###############################################################
#  Generated by:      Cadence Innovus 21.14-s109_1
#  OS:                Linux x86_64(Host ID eecs2420p06.engin.umich.edu)
#  Generated on:      Fri Mar 24 00:08:22 2023
#  Design:            PE_top
#  Command:           write_lef_abstract /afs/umich.edu/class/eecs627/w23/groups/group4/CNN_LSTM/CNN/apr/PE_top/data/PE_top.lef -specifyTopLayer 4 -stripePin -PGpinLayers 4
###############################################################

VERSION 5.8 ;

BUSBITCHARS "[]" ;
DIVIDERCHAR "/" ;

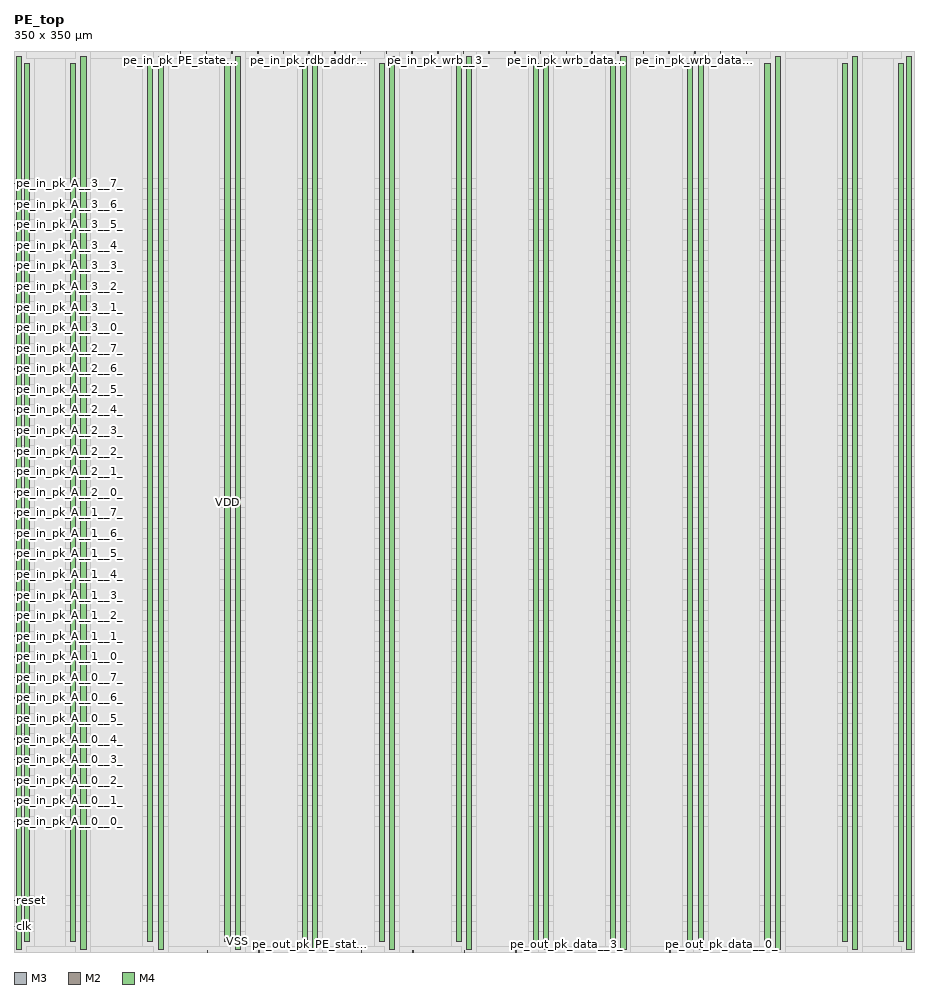
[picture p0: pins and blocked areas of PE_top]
MACRO PE_top
  CLASS BLOCK ;
  SIZE 350.000000 BY 350.000000 ;
  FOREIGN PE_top 0.000000 0.000000 ;
  ORIGIN 0 0 ;
  SYMMETRY X Y R90 ;
  PIN clk
    DIRECTION INPUT ;
    USE SIGNAL ;
    ANTENNAPARTIALMETALAREA 1.38 LAYER M3  ;
    ANTENNAPARTIALMETALSIDEAREA 0.0142 LAYER M3  ;
    ANTENNAMODEL OXIDE1 ;
    ANTENNAGATEAREA 0.8352 LAYER M3  ;
    ANTENNAMAXAREACAR 2.64655 LAYER M3  ;
    ANTENNAMAXSIDEAREACAR 0.0272749 LAYER M3  ;
    ANTENNAMAXCUTCAR 0.191571 LAYER V3  ;
    PORT
      LAYER M3 ;
        RECT 0.000000 9.900000 0.600000 10.100000 ;
    END
  END clk
  PIN reset
    DIRECTION INPUT ;
    USE SIGNAL ;
    ANTENNAPARTIALMETALAREA 4.46 LAYER M3  ;
    ANTENNAPARTIALMETALSIDEAREA 0.0454 LAYER M3  ;
    ANTENNAMODEL OXIDE1 ;
    ANTENNAGATEAREA 0.9552 LAYER M3  ;
    ANTENNAMAXAREACAR 56.4025 LAYER M3  ;
    ANTENNAMAXSIDEAREACAR 0.569324 LAYER M3  ;
    ANTENNAMAXCUTCAR 1.28205 LAYER V3  ;
    PORT
      LAYER M3 ;
        RECT 0.000000 19.900000 0.600000 20.100000 ;
    END
  END reset
  PIN pe_in_pk_PE_state__2_
    DIRECTION INPUT ;
    USE SIGNAL ;
    ANTENNAPARTIALMETALAREA 5.98 LAYER M2  ;
    ANTENNAPARTIALMETALSIDEAREA 0.0598 LAYER M2  ;
    ANTENNAPARTIALCUTAREA 0.04 LAYER V2  ;
    ANTENNAPARTIALMETALAREA 0.24 LAYER M3  ;
    ANTENNAPARTIALMETALSIDEAREA 0.0032 LAYER M3  ;
    ANTENNAMODEL OXIDE1 ;
    ANTENNAGATEAREA 0.0624 LAYER M3  ;
    ANTENNAMAXAREACAR 33.8462 LAYER M3  ;
    ANTENNAMAXSIDEAREACAR 0.358333 LAYER M3  ;
    ANTENNAMAXCUTCAR 1.28205 LAYER V3  ;
    PORT
      LAYER M2 ;
        RECT 84.700000 349.400000 84.900000 350.000000 ;
    END
  END pe_in_pk_PE_state__2_
  PIN pe_in_pk_PE_state__1_
    DIRECTION INPUT ;
    USE SIGNAL ;
    ANTENNAPARTIALMETALAREA 5.1 LAYER M2  ;
    ANTENNAPARTIALMETALSIDEAREA 0.051 LAYER M2  ;
    ANTENNAPARTIALCUTAREA 0.08 LAYER V2  ;
    ANTENNAPARTIALMETALAREA 1.24 LAYER M3  ;
    ANTENNAPARTIALMETALSIDEAREA 0.0128 LAYER M3  ;
    ANTENNAMODEL OXIDE1 ;
    ANTENNAGATEAREA 0.0624 LAYER M3  ;
    ANTENNAMAXAREACAR 87.0513 LAYER M3  ;
    ANTENNAMAXSIDEAREACAR 0.883974 LAYER M3  ;
    ANTENNAMAXCUTCAR 1.92308 LAYER V3  ;
    PORT
      LAYER M2 ;
        RECT 74.700000 349.400000 74.900000 350.000000 ;
    END
  END pe_in_pk_PE_state__1_
  PIN pe_in_pk_PE_state__0_
    DIRECTION INPUT ;
    USE SIGNAL ;
    ANTENNAPARTIALMETALAREA 5.26 LAYER M2  ;
    ANTENNAPARTIALMETALSIDEAREA 0.0526 LAYER M2  ;
    ANTENNAPARTIALCUTAREA 0.08 LAYER V2  ;
    ANTENNAPARTIALMETALAREA 2.6 LAYER M3  ;
    ANTENNAPARTIALMETALSIDEAREA 0.0264 LAYER M3  ;
    ANTENNAMODEL OXIDE1 ;
    ANTENNAGATEAREA 0.0624 LAYER M3  ;
    ANTENNAMAXAREACAR 106.282 LAYER M3  ;
    ANTENNAMAXSIDEAREACAR 1.07628 LAYER M3  ;
    ANTENNAMAXCUTCAR 1.92308 LAYER V3  ;
    PORT
      LAYER M2 ;
        RECT 64.700000 349.400000 64.900000 350.000000 ;
    END
  END pe_in_pk_PE_state__0_
  PIN pe_in_pk_A__3__7_
    DIRECTION INPUT ;
    USE SIGNAL ;
    ANTENNAPARTIALMETALAREA 8.54 LAYER M3  ;
    ANTENNAPARTIALMETALSIDEAREA 0.0854 LAYER M3  ;
    ANTENNAMODEL OXIDE1 ;
    ANTENNAGATEAREA 0.0624 LAYER M3  ;
    ANTENNAMAXAREACAR 169.423 LAYER M3  ;
    ANTENNAMAXSIDEAREACAR 1.70128 LAYER M3  ;
    ANTENNAMAXCUTCAR 1.92308 LAYER V3  ;
    PORT
      LAYER M3 ;
        RECT 0.000000 298.700000 0.600000 298.900000 ;
    END
  END pe_in_pk_A__3__7_
  PIN pe_in_pk_A__3__6_
    DIRECTION INPUT ;
    USE SIGNAL ;
    ANTENNAPARTIALMETALAREA 7.58 LAYER M3  ;
    ANTENNAPARTIALMETALSIDEAREA 0.0758 LAYER M3  ;
    ANTENNAMODEL OXIDE1 ;
    ANTENNAGATEAREA 0.0624 LAYER M3  ;
    ANTENNAMAXAREACAR 127.115 LAYER M3  ;
    ANTENNAMAXSIDEAREACAR 1.27821 LAYER M3  ;
    ANTENNAMAXCUTCAR 1.92308 LAYER V3  ;
    PORT
      LAYER M3 ;
        RECT 0.000000 290.700000 0.600000 290.900000 ;
    END
  END pe_in_pk_A__3__6_
  PIN pe_in_pk_A__3__5_
    DIRECTION INPUT ;
    USE SIGNAL ;
    ANTENNAPARTIALMETALAREA 6.54 LAYER M3  ;
    ANTENNAPARTIALMETALSIDEAREA 0.0654 LAYER M3  ;
    ANTENNAMODEL OXIDE1 ;
    ANTENNAGATEAREA 0.0624 LAYER M3  ;
    ANTENNAMAXAREACAR 121.987 LAYER M3  ;
    ANTENNAMAXSIDEAREACAR 1.22692 LAYER M3  ;
    ANTENNAMAXCUTCAR 1.92308 LAYER V3  ;
    PORT
      LAYER M3 ;
        RECT 0.000000 282.700000 0.600000 282.900000 ;
    END
  END pe_in_pk_A__3__5_
  PIN pe_in_pk_A__3__4_
    DIRECTION INPUT ;
    USE SIGNAL ;
    ANTENNAPARTIALMETALAREA 6.14 LAYER M3  ;
    ANTENNAPARTIALMETALSIDEAREA 0.0614 LAYER M3  ;
    ANTENNAMODEL OXIDE1 ;
    ANTENNAGATEAREA 0.0624 LAYER M3  ;
    ANTENNAMAXAREACAR 113.013 LAYER M3  ;
    ANTENNAMAXSIDEAREACAR 1.13718 LAYER M3  ;
    ANTENNAMAXCUTCAR 1.92308 LAYER V3  ;
    PORT
      LAYER M3 ;
        RECT 0.000000 274.700000 0.600000 274.900000 ;
    END
  END pe_in_pk_A__3__4_
  PIN pe_in_pk_A__3__3_
    DIRECTION INPUT ;
    USE SIGNAL ;
    ANTENNAPARTIALMETALAREA 6.14 LAYER M3  ;
    ANTENNAPARTIALMETALSIDEAREA 0.0614 LAYER M3  ;
    ANTENNAMODEL OXIDE1 ;
    ANTENNAGATEAREA 0.0624 LAYER M3  ;
    ANTENNAMAXAREACAR 106.603 LAYER M3  ;
    ANTENNAMAXSIDEAREACAR 1.07308 LAYER M3  ;
    ANTENNAMAXCUTCAR 1.92308 LAYER V3  ;
    PORT
      LAYER M3 ;
        RECT 0.000000 266.700000 0.600000 266.900000 ;
    END
  END pe_in_pk_A__3__3_
  PIN pe_in_pk_A__3__2_
    DIRECTION INPUT ;
    USE SIGNAL ;
    ANTENNAPARTIALMETALAREA 6.22 LAYER M3  ;
    ANTENNAPARTIALMETALSIDEAREA 0.0622 LAYER M3  ;
    ANTENNAMODEL OXIDE1 ;
    ANTENNAGATEAREA 0.0624 LAYER M3  ;
    ANTENNAMAXAREACAR 107.885 LAYER M3  ;
    ANTENNAMAXSIDEAREACAR 1.0859 LAYER M3  ;
    ANTENNAMAXCUTCAR 1.92308 LAYER V3  ;
    PORT
      LAYER M3 ;
        RECT 0.000000 258.700000 0.600000 258.900000 ;
    END
  END pe_in_pk_A__3__2_
  PIN pe_in_pk_A__3__1_
    DIRECTION INPUT ;
    USE SIGNAL ;
    ANTENNAPARTIALMETALAREA 6.38 LAYER M3  ;
    ANTENNAPARTIALMETALSIDEAREA 0.0638 LAYER M3  ;
    ANTENNAMODEL OXIDE1 ;
    ANTENNAGATEAREA 0.0624 LAYER M3  ;
    ANTENNAMAXAREACAR 109.167 LAYER M3  ;
    ANTENNAMAXSIDEAREACAR 1.09872 LAYER M3  ;
    ANTENNAMAXCUTCAR 1.92308 LAYER V3  ;
    PORT
      LAYER M3 ;
        RECT 0.000000 250.700000 0.600000 250.900000 ;
    END
  END pe_in_pk_A__3__1_
  PIN pe_in_pk_A__3__0_
    DIRECTION INPUT ;
    USE SIGNAL ;
    ANTENNAPARTIALMETALAREA 6.38 LAYER M3  ;
    ANTENNAPARTIALMETALSIDEAREA 0.0638 LAYER M3  ;
    ANTENNAMODEL OXIDE1 ;
    ANTENNAGATEAREA 0.0624 LAYER M3  ;
    ANTENNAMAXAREACAR 106.603 LAYER M3  ;
    ANTENNAMAXSIDEAREACAR 1.07308 LAYER M3  ;
    ANTENNAMAXCUTCAR 1.92308 LAYER V3  ;
    PORT
      LAYER M3 ;
        RECT 0.000000 242.700000 0.600000 242.900000 ;
    END
  END pe_in_pk_A__3__0_
  PIN pe_in_pk_A__2__7_
    DIRECTION INPUT ;
    USE SIGNAL ;
    ANTENNAPARTIALMETALAREA 6.46 LAYER M3  ;
    ANTENNAPARTIALMETALSIDEAREA 0.0646 LAYER M3  ;
    ANTENNAMODEL OXIDE1 ;
    ANTENNAGATEAREA 0.0624 LAYER M3  ;
    ANTENNAMAXAREACAR 114.295 LAYER M3  ;
    ANTENNAMAXSIDEAREACAR 1.15 LAYER M3  ;
    ANTENNAMAXCUTCAR 1.92308 LAYER V3  ;
    PORT
      LAYER M3 ;
        RECT 0.000000 234.700000 0.600000 234.900000 ;
    END
  END pe_in_pk_A__2__7_
  PIN pe_in_pk_A__2__6_
    DIRECTION INPUT ;
    USE SIGNAL ;
    ANTENNAPARTIALMETALAREA 6.62 LAYER M3  ;
    ANTENNAPARTIALMETALSIDEAREA 0.0662 LAYER M3  ;
    ANTENNAMODEL OXIDE1 ;
    ANTENNAGATEAREA 0.0624 LAYER M3  ;
    ANTENNAMAXAREACAR 115.577 LAYER M3  ;
    ANTENNAMAXSIDEAREACAR 1.16282 LAYER M3  ;
    ANTENNAMAXCUTCAR 1.92308 LAYER V3  ;
    PORT
      LAYER M3 ;
        RECT 0.000000 226.700000 0.600000 226.900000 ;
    END
  END pe_in_pk_A__2__6_
  PIN pe_in_pk_A__2__5_
    DIRECTION INPUT ;
    USE SIGNAL ;
    ANTENNAPARTIALMETALAREA 6.46 LAYER M3  ;
    ANTENNAPARTIALMETALSIDEAREA 0.0646 LAYER M3  ;
    ANTENNAMODEL OXIDE1 ;
    ANTENNAGATEAREA 0.0624 LAYER M3  ;
    ANTENNAMAXAREACAR 113.013 LAYER M3  ;
    ANTENNAMAXSIDEAREACAR 1.13718 LAYER M3  ;
    ANTENNAMAXCUTCAR 1.92308 LAYER V3  ;
    PORT
      LAYER M3 ;
        RECT 0.000000 218.700000 0.600000 218.900000 ;
    END
  END pe_in_pk_A__2__5_
  PIN pe_in_pk_A__2__4_
    DIRECTION INPUT ;
    USE SIGNAL ;
    ANTENNAPARTIALMETALAREA 6.46 LAYER M3  ;
    ANTENNAPARTIALMETALSIDEAREA 0.0646 LAYER M3  ;
    ANTENNAMODEL OXIDE1 ;
    ANTENNAGATEAREA 0.0624 LAYER M3  ;
    ANTENNAMAXAREACAR 107.885 LAYER M3  ;
    ANTENNAMAXSIDEAREACAR 1.0859 LAYER M3  ;
    ANTENNAMAXCUTCAR 1.92308 LAYER V3  ;
    PORT
      LAYER M3 ;
        RECT 0.000000 210.700000 0.600000 210.900000 ;
    END
  END pe_in_pk_A__2__4_
  PIN pe_in_pk_A__2__3_
    DIRECTION INPUT ;
    USE SIGNAL ;
    ANTENNAPARTIALMETALAREA 6.54 LAYER M3  ;
    ANTENNAPARTIALMETALSIDEAREA 0.0654 LAYER M3  ;
    ANTENNAMODEL OXIDE1 ;
    ANTENNAGATEAREA 0.0624 LAYER M3  ;
    ANTENNAMAXAREACAR 110.449 LAYER M3  ;
    ANTENNAMAXSIDEAREACAR 1.11154 LAYER M3  ;
    ANTENNAMAXCUTCAR 1.92308 LAYER V3  ;
    PORT
      LAYER M3 ;
        RECT 0.000000 202.700000 0.600000 202.900000 ;
    END
  END pe_in_pk_A__2__3_
  PIN pe_in_pk_A__2__2_
    DIRECTION INPUT ;
    USE SIGNAL ;
    ANTENNAPARTIALMETALAREA 5.1 LAYER M3  ;
    ANTENNAPARTIALMETALSIDEAREA 0.051 LAYER M3  ;
    ANTENNAMODEL OXIDE1 ;
    ANTENNAGATEAREA 0.0624 LAYER M3  ;
    ANTENNAMAXAREACAR 91.2179 LAYER M3  ;
    ANTENNAMAXSIDEAREACAR 0.919231 LAYER M3  ;
    ANTENNAMAXCUTCAR 1.92308 LAYER V3  ;
    PORT
      LAYER M3 ;
        RECT 0.000000 194.700000 0.600000 194.900000 ;
    END
  END pe_in_pk_A__2__2_
  PIN pe_in_pk_A__2__1_
    DIRECTION INPUT ;
    USE SIGNAL ;
    ANTENNAPARTIALMETALAREA 4.06 LAYER M3  ;
    ANTENNAPARTIALMETALSIDEAREA 0.0406 LAYER M3  ;
    ANTENNAMODEL OXIDE1 ;
    ANTENNAGATEAREA 0.0624 LAYER M3  ;
    ANTENNAMAXAREACAR 74.5513 LAYER M3  ;
    ANTENNAMAXSIDEAREACAR 0.752564 LAYER M3  ;
    ANTENNAMAXCUTCAR 1.92308 LAYER V3  ;
    PORT
      LAYER M3 ;
        RECT 0.000000 186.700000 0.600000 186.900000 ;
    END
  END pe_in_pk_A__2__1_
  PIN pe_in_pk_A__2__0_
    DIRECTION INPUT ;
    USE SIGNAL ;
    ANTENNAPARTIALMETALAREA 3.34 LAYER M3  ;
    ANTENNAPARTIALMETALSIDEAREA 0.0334 LAYER M3  ;
    ANTENNAMODEL OXIDE1 ;
    ANTENNAGATEAREA 0.0624 LAYER M3  ;
    ANTENNAMAXAREACAR 66.859 LAYER M3  ;
    ANTENNAMAXSIDEAREACAR 0.675641 LAYER M3  ;
    ANTENNAMAXCUTCAR 1.92308 LAYER V3  ;
    PORT
      LAYER M3 ;
        RECT 0.000000 178.700000 0.600000 178.900000 ;
    END
  END pe_in_pk_A__2__0_
  PIN pe_in_pk_A__1__7_
    DIRECTION INPUT ;
    USE SIGNAL ;
    ANTENNAPARTIALMETALAREA 2.22 LAYER M3  ;
    ANTENNAPARTIALMETALSIDEAREA 0.0222 LAYER M3  ;
    ANTENNAMODEL OXIDE1 ;
    ANTENNAGATEAREA 0.0624 LAYER M3  ;
    ANTENNAMAXAREACAR 48.9103 LAYER M3  ;
    ANTENNAMAXSIDEAREACAR 0.496154 LAYER M3  ;
    ANTENNAMAXCUTCAR 1.92308 LAYER V3  ;
    PORT
      LAYER M3 ;
        RECT 0.000000 170.700000 0.600000 170.900000 ;
    END
  END pe_in_pk_A__1__7_
  PIN pe_in_pk_A__1__6_
    DIRECTION INPUT ;
    USE SIGNAL ;
    ANTENNAPARTIALMETALAREA 1.58 LAYER M3  ;
    ANTENNAPARTIALMETALSIDEAREA 0.0158 LAYER M3  ;
    ANTENNAMODEL OXIDE1 ;
    ANTENNAGATEAREA 0.0624 LAYER M3  ;
    ANTENNAMAXAREACAR 30.9615 LAYER M3  ;
    ANTENNAMAXSIDEAREACAR 0.316667 LAYER M3  ;
    ANTENNAMAXCUTCAR 1.92308 LAYER V3  ;
    PORT
      LAYER M3 ;
        RECT 0.000000 162.700000 0.600000 162.900000 ;
    END
  END pe_in_pk_A__1__6_
  PIN pe_in_pk_A__1__5_
    DIRECTION INPUT ;
    USE SIGNAL ;
    ANTENNAPARTIALMETALAREA 1.66 LAYER M3  ;
    ANTENNAPARTIALMETALSIDEAREA 0.0166 LAYER M3  ;
    ANTENNAMODEL OXIDE1 ;
    ANTENNAGATEAREA 0.0624 LAYER M3  ;
    ANTENNAMAXAREACAR 34.8077 LAYER M3  ;
    ANTENNAMAXSIDEAREACAR 0.355128 LAYER M3  ;
    ANTENNAMAXCUTCAR 1.92308 LAYER V3  ;
    PORT
      LAYER M3 ;
        RECT 0.000000 154.700000 0.600000 154.900000 ;
    END
  END pe_in_pk_A__1__5_
  PIN pe_in_pk_A__1__4_
    DIRECTION INPUT ;
    USE SIGNAL ;
    ANTENNAPARTIALMETALAREA 1.74 LAYER M3  ;
    ANTENNAPARTIALMETALSIDEAREA 0.0174 LAYER M3  ;
    ANTENNAMODEL OXIDE1 ;
    ANTENNAGATEAREA 0.0624 LAYER M3  ;
    ANTENNAMAXAREACAR 33.5256 LAYER M3  ;
    ANTENNAMAXSIDEAREACAR 0.342308 LAYER M3  ;
    ANTENNAMAXCUTCAR 1.92308 LAYER V3  ;
    PORT
      LAYER M3 ;
        RECT 0.000000 146.700000 0.600000 146.900000 ;
    END
  END pe_in_pk_A__1__4_
  PIN pe_in_pk_A__1__3_
    DIRECTION INPUT ;
    USE SIGNAL ;
    ANTENNAPARTIALMETALAREA 1.66 LAYER M3  ;
    ANTENNAPARTIALMETALSIDEAREA 0.0166 LAYER M3  ;
    ANTENNAMODEL OXIDE1 ;
    ANTENNAGATEAREA 0.0624 LAYER M3  ;
    ANTENNAMAXAREACAR 30.9615 LAYER M3  ;
    ANTENNAMAXSIDEAREACAR 0.316667 LAYER M3  ;
    ANTENNAMAXCUTCAR 1.92308 LAYER V3  ;
    PORT
      LAYER M3 ;
        RECT 0.000000 138.700000 0.600000 138.900000 ;
    END
  END pe_in_pk_A__1__3_
  PIN pe_in_pk_A__1__2_
    DIRECTION INPUT ;
    USE SIGNAL ;
    ANTENNAPARTIALMETALAREA 1.74 LAYER M3  ;
    ANTENNAPARTIALMETALSIDEAREA 0.0174 LAYER M3  ;
    ANTENNAMODEL OXIDE1 ;
    ANTENNAGATEAREA 0.0624 LAYER M3  ;
    ANTENNAMAXAREACAR 45.0641 LAYER M3  ;
    ANTENNAMAXSIDEAREACAR 0.457692 LAYER M3  ;
    ANTENNAMAXCUTCAR 1.92308 LAYER V3  ;
    PORT
      LAYER M3 ;
        RECT 0.000000 130.700000 0.600000 130.900000 ;
    END
  END pe_in_pk_A__1__2_
  PIN pe_in_pk_A__1__1_
    DIRECTION INPUT ;
    USE SIGNAL ;
    ANTENNAPARTIALMETALAREA 1.74 LAYER M3  ;
    ANTENNAPARTIALMETALSIDEAREA 0.0174 LAYER M3  ;
    ANTENNAMODEL OXIDE1 ;
    ANTENNAGATEAREA 0.0624 LAYER M3  ;
    ANTENNAMAXAREACAR 39.9359 LAYER M3  ;
    ANTENNAMAXSIDEAREACAR 0.40641 LAYER M3  ;
    ANTENNAMAXCUTCAR 1.92308 LAYER V3  ;
    PORT
      LAYER M3 ;
        RECT 0.000000 122.700000 0.600000 122.900000 ;
    END
  END pe_in_pk_A__1__1_
  PIN pe_in_pk_A__1__0_
    DIRECTION INPUT ;
    USE SIGNAL ;
    ANTENNAPARTIALMETALAREA 2.54 LAYER M3  ;
    ANTENNAPARTIALMETALSIDEAREA 0.0254 LAYER M3  ;
    ANTENNAMODEL OXIDE1 ;
    ANTENNAGATEAREA 0.0624 LAYER M3  ;
    ANTENNAMAXAREACAR 50.1923 LAYER M3  ;
    ANTENNAMAXSIDEAREACAR 0.508974 LAYER M3  ;
    ANTENNAMAXCUTCAR 1.92308 LAYER V3  ;
    PORT
      LAYER M3 ;
        RECT 0.000000 114.700000 0.600000 114.900000 ;
    END
  END pe_in_pk_A__1__0_
  PIN pe_in_pk_A__0__7_
    DIRECTION INPUT ;
    USE SIGNAL ;
    ANTENNAPARTIALMETALAREA 3.34 LAYER M3  ;
    ANTENNAPARTIALMETALSIDEAREA 0.0334 LAYER M3  ;
    ANTENNAMODEL OXIDE1 ;
    ANTENNAGATEAREA 0.0624 LAYER M3  ;
    ANTENNAMAXAREACAR 60.4487 LAYER M3  ;
    ANTENNAMAXSIDEAREACAR 0.611538 LAYER M3  ;
    ANTENNAMAXCUTCAR 1.92308 LAYER V3  ;
    PORT
      LAYER M3 ;
        RECT 0.000000 106.700000 0.600000 106.900000 ;
    END
  END pe_in_pk_A__0__7_
  PIN pe_in_pk_A__0__6_
    DIRECTION INPUT ;
    USE SIGNAL ;
    ANTENNAPARTIALMETALAREA 3.34 LAYER M3  ;
    ANTENNAPARTIALMETALSIDEAREA 0.0334 LAYER M3  ;
    ANTENNAMODEL OXIDE1 ;
    ANTENNAGATEAREA 0.0624 LAYER M3  ;
    ANTENNAMAXAREACAR 66.859 LAYER M3  ;
    ANTENNAMAXSIDEAREACAR 0.675641 LAYER M3  ;
    ANTENNAMAXCUTCAR 1.92308 LAYER V3  ;
    PORT
      LAYER M3 ;
        RECT 0.000000 98.700000 0.600000 98.900000 ;
    END
  END pe_in_pk_A__0__6_
  PIN pe_in_pk_A__0__5_
    DIRECTION INPUT ;
    USE SIGNAL ;
    ANTENNAPARTIALMETALAREA 3.58 LAYER M3  ;
    ANTENNAPARTIALMETALSIDEAREA 0.0358 LAYER M3  ;
    ANTENNAMODEL OXIDE1 ;
    ANTENNAGATEAREA 0.0624 LAYER M3  ;
    ANTENNAMAXAREACAR 68.141 LAYER M3  ;
    ANTENNAMAXSIDEAREACAR 0.688462 LAYER M3  ;
    ANTENNAMAXCUTCAR 1.92308 LAYER V3  ;
    PORT
      LAYER M3 ;
        RECT 0.000000 90.700000 0.600000 90.900000 ;
    END
  END pe_in_pk_A__0__5_
  PIN pe_in_pk_A__0__4_
    DIRECTION INPUT ;
    USE SIGNAL ;
    ANTENNAPARTIALMETALAREA 3.9 LAYER M3  ;
    ANTENNAPARTIALMETALSIDEAREA 0.039 LAYER M3  ;
    ANTENNAMODEL OXIDE1 ;
    ANTENNAGATEAREA 0.0624 LAYER M3  ;
    ANTENNAMAXAREACAR 70.7051 LAYER M3  ;
    ANTENNAMAXSIDEAREACAR 0.714103 LAYER M3  ;
    ANTENNAMAXCUTCAR 1.92308 LAYER V3  ;
    PORT
      LAYER M3 ;
        RECT 0.000000 82.700000 0.600000 82.900000 ;
    END
  END pe_in_pk_A__0__4_
  PIN pe_in_pk_A__0__3_
    DIRECTION INPUT ;
    USE SIGNAL ;
    ANTENNAPARTIALMETALAREA 4.3 LAYER M3  ;
    ANTENNAPARTIALMETALSIDEAREA 0.043 LAYER M3  ;
    ANTENNAMODEL OXIDE1 ;
    ANTENNAGATEAREA 0.0624 LAYER M3  ;
    ANTENNAMAXAREACAR 74.5513 LAYER M3  ;
    ANTENNAMAXSIDEAREACAR 0.752564 LAYER M3  ;
    ANTENNAMAXCUTCAR 1.92308 LAYER V3  ;
    PORT
      LAYER M3 ;
        RECT 0.000000 74.700000 0.600000 74.900000 ;
    END
  END pe_in_pk_A__0__3_
  PIN pe_in_pk_A__0__2_
    DIRECTION INPUT ;
    USE SIGNAL ;
    ANTENNAPARTIALMETALAREA 2.06 LAYER M3  ;
    ANTENNAPARTIALMETALSIDEAREA 0.0206 LAYER M3  ;
    ANTENNAMODEL OXIDE1 ;
    ANTENNAGATEAREA 0.0624 LAYER M3  ;
    ANTENNAMAXAREACAR 59.1667 LAYER M3  ;
    ANTENNAMAXSIDEAREACAR 0.598718 LAYER M3  ;
    ANTENNAMAXCUTCAR 1.92308 LAYER V3  ;
    PORT
      LAYER M3 ;
        RECT 0.000000 66.700000 0.600000 66.900000 ;
    END
  END pe_in_pk_A__0__2_
  PIN pe_in_pk_A__0__1_
    DIRECTION INPUT ;
    USE SIGNAL ;
    ANTENNAPARTIALMETALAREA 2.06 LAYER M3  ;
    ANTENNAPARTIALMETALSIDEAREA 0.0206 LAYER M3  ;
    ANTENNAPARTIALCUTAREA 0.08 LAYER V3  ;
    ANTENNAPARTIALMETALAREA 0.36 LAYER M4  ;
    ANTENNAPARTIALMETALSIDEAREA 0.004 LAYER M4  ;
    ANTENNAMODEL OXIDE1 ;
    ANTENNAGATEAREA 0.0624 LAYER M4  ;
    ANTENNAMAXAREACAR 55.641 LAYER M4  ;
    ANTENNAMAXSIDEAREACAR 0.576282 LAYER M4  ;
    ANTENNAMAXCUTCAR 3.20513 LAYER V4  ;
    PORT
      LAYER M3 ;
        RECT 0.000000 58.700000 0.600000 58.900000 ;
    END
  END pe_in_pk_A__0__1_
  PIN pe_in_pk_A__0__0_
    DIRECTION INPUT ;
    USE SIGNAL ;
    ANTENNAPARTIALMETALAREA 4.78 LAYER M3  ;
    ANTENNAPARTIALMETALSIDEAREA 0.0478 LAYER M3  ;
    ANTENNAMODEL OXIDE1 ;
    ANTENNAGATEAREA 0.0624 LAYER M3  ;
    ANTENNAMAXAREACAR 133.526 LAYER M3  ;
    ANTENNAMAXSIDEAREACAR 1.34231 LAYER M3  ;
    ANTENNAMAXCUTCAR 1.92308 LAYER V3  ;
    PORT
      LAYER M3 ;
        RECT 0.000000 50.700000 0.600000 50.900000 ;
    END
  END pe_in_pk_A__0__0_
  PIN pe_in_pk_wrb_data__7_
    DIRECTION INPUT ;
    USE SIGNAL ;
    ANTENNAPARTIALMETALAREA 11.82 LAYER M2  ;
    ANTENNAPARTIALMETALSIDEAREA 0.1182 LAYER M2  ;
    ANTENNAPARTIALCUTAREA 0.08 LAYER V2  ;
    ANTENNAPARTIALMETALAREA 7.56 LAYER M3  ;
    ANTENNAPARTIALMETALSIDEAREA 0.076 LAYER M3  ;
    ANTENNAPARTIALCUTAREA 0.04 LAYER V3  ;
    ANTENNAPARTIALMETALAREA 19.12 LAYER M4  ;
    ANTENNAPARTIALMETALSIDEAREA 0.1928 LAYER M4  ;
    ANTENNAMODEL OXIDE1 ;
    ANTENNAGATEAREA 0.3792 LAYER M4  ;
    ANTENNAMAXAREACAR 111.191 LAYER M4  ;
    ANTENNAMAXSIDEAREACAR 1.136 LAYER M4  ;
    ANTENNAMAXCUTCAR 5.76923 LAYER V4  ;
    PORT
      LAYER M2 ;
        RECT 284.700000 349.400000 284.900000 350.000000 ;
    END
  END pe_in_pk_wrb_data__7_
  PIN pe_in_pk_wrb_data__6_
    DIRECTION INPUT ;
    USE SIGNAL ;
    ANTENNAPARTIALMETALAREA 8.86 LAYER M2  ;
    ANTENNAPARTIALMETALSIDEAREA 0.0886 LAYER M2  ;
    ANTENNAPARTIALCUTAREA 0.08 LAYER V2  ;
    ANTENNAPARTIALMETALAREA 9.48 LAYER M3  ;
    ANTENNAPARTIALMETALSIDEAREA 0.0952 LAYER M3  ;
    ANTENNAMODEL OXIDE1 ;
    ANTENNAGATEAREA 0.1272 LAYER M3  ;
    ANTENNAMAXAREACAR 78.3648 LAYER M3  ;
    ANTENNAMAXSIDEAREACAR 0.789937 LAYER M3  ;
    ANTENNAPARTIALCUTAREA 0.08 LAYER V3  ;
    ANTENNAMAXCUTCAR 1.88679 LAYER V3  ;
    ANTENNAPARTIALMETALAREA 24.44 LAYER M4  ;
    ANTENNAPARTIALMETALSIDEAREA 0.2448 LAYER M4  ;
    ANTENNAGATEAREA 0.444 LAYER M4  ;
    ANTENNAMAXAREACAR 133.41 LAYER M4  ;
    ANTENNAMAXSIDEAREACAR 1.34129 LAYER M4  ;
    ANTENNAMAXCUTCAR 3.20513 LAYER V4  ;
    PORT
      LAYER M2 ;
        RECT 274.700000 349.400000 274.900000 350.000000 ;
    END
  END pe_in_pk_wrb_data__6_
  PIN pe_in_pk_wrb_data__5_
    DIRECTION INPUT ;
    USE SIGNAL ;
    ANTENNAPARTIALMETALAREA 8.54 LAYER M2  ;
    ANTENNAPARTIALMETALSIDEAREA 0.0854 LAYER M2  ;
    ANTENNAPARTIALCUTAREA 0.08 LAYER V2  ;
    ANTENNAPARTIALMETALAREA 8.24 LAYER M3  ;
    ANTENNAPARTIALMETALSIDEAREA 0.0832 LAYER M3  ;
    ANTENNAMODEL OXIDE1 ;
    ANTENNAGATEAREA 0.0624 LAYER M3  ;
    ANTENNAMAXAREACAR 151.795 LAYER M3  ;
    ANTENNAMAXSIDEAREACAR 1.53782 LAYER M3  ;
    ANTENNAPARTIALCUTAREA 0.08 LAYER V3  ;
    ANTENNAMAXCUTCAR 4.48718 LAYER V3  ;
    ANTENNAPARTIALMETALAREA 26 LAYER M4  ;
    ANTENNAPARTIALMETALSIDEAREA 0.2608 LAYER M4  ;
    ANTENNAGATEAREA 0.3792 LAYER M4  ;
    ANTENNAMAXAREACAR 220.36 LAYER M4  ;
    ANTENNAMAXSIDEAREACAR 2.22558 LAYER M4  ;
    ANTENNAMAXCUTCAR 4.48718 LAYER V4  ;
    PORT
      LAYER M2 ;
        RECT 264.700000 349.400000 264.900000 350.000000 ;
    END
  END pe_in_pk_wrb_data__5_
  PIN pe_in_pk_wrb_data__4_
    DIRECTION INPUT ;
    USE SIGNAL ;
    ANTENNAPARTIALMETALAREA 17.18 LAYER M2  ;
    ANTENNAPARTIALMETALSIDEAREA 0.1718 LAYER M2  ;
    ANTENNAPARTIALCUTAREA 0.08 LAYER V2  ;
    ANTENNAPARTIALMETALAREA 6.36 LAYER M3  ;
    ANTENNAPARTIALMETALSIDEAREA 0.064 LAYER M3  ;
    ANTENNAMODEL OXIDE1 ;
    ANTENNAGATEAREA 0.1272 LAYER M3  ;
    ANTENNAMAXAREACAR 53.8365 LAYER M3  ;
    ANTENNAMAXSIDEAREACAR 0.544654 LAYER M3  ;
    ANTENNAPARTIALCUTAREA 0.08 LAYER V3  ;
    ANTENNAMAXCUTCAR 1.88679 LAYER V3  ;
    ANTENNAPARTIALMETALAREA 16.24 LAYER M4  ;
    ANTENNAPARTIALMETALSIDEAREA 0.1632 LAYER M4  ;
    ANTENNAGATEAREA 0.444 LAYER M4  ;
    ANTENNAMAXAREACAR 90.4131 LAYER M4  ;
    ANTENNAMAXSIDEAREACAR 0.912222 LAYER M4  ;
    ANTENNAMAXCUTCAR 4.48718 LAYER V4  ;
    PORT
      LAYER M2 ;
        RECT 254.700000 349.400000 254.900000 350.000000 ;
    END
  END pe_in_pk_wrb_data__4_
  PIN pe_in_pk_wrb_data__3_
    DIRECTION INPUT ;
    USE SIGNAL ;
    ANTENNAPARTIALMETALAREA 16.78 LAYER M2  ;
    ANTENNAPARTIALMETALSIDEAREA 0.1678 LAYER M2  ;
    ANTENNAPARTIALCUTAREA 0.08 LAYER V2  ;
    ANTENNAPARTIALMETALAREA 4.2 LAYER M3  ;
    ANTENNAPARTIALMETALSIDEAREA 0.0424 LAYER M3  ;
    ANTENNAMODEL OXIDE1 ;
    ANTENNAGATEAREA 0.0624 LAYER M3  ;
    ANTENNAMAXAREACAR 78.0769 LAYER M3  ;
    ANTENNAMAXSIDEAREACAR 0.794231 LAYER M3  ;
    ANTENNAPARTIALCUTAREA 0.08 LAYER V3  ;
    ANTENNAMAXCUTCAR 3.20513 LAYER V3  ;
    ANTENNAPARTIALMETALAREA 18.12 LAYER M4  ;
    ANTENNAPARTIALMETALSIDEAREA 0.1816 LAYER M4  ;
    ANTENNAGATEAREA 0.3792 LAYER M4  ;
    ANTENNAMAXAREACAR 125.862 LAYER M4  ;
    ANTENNAMAXSIDEAREACAR 1.27313 LAYER M4  ;
    ANTENNAMAXCUTCAR 3.20513 LAYER V4  ;
    PORT
      LAYER M2 ;
        RECT 244.700000 349.400000 244.900000 350.000000 ;
    END
  END pe_in_pk_wrb_data__3_
  PIN pe_in_pk_wrb_data__2_
    DIRECTION INPUT ;
    USE SIGNAL ;
    ANTENNAPARTIALMETALAREA 5.74 LAYER M2  ;
    ANTENNAPARTIALMETALSIDEAREA 0.0574 LAYER M2  ;
    ANTENNAPARTIALCUTAREA 0.08 LAYER V2  ;
    ANTENNAPARTIALMETALAREA 3.08 LAYER M3  ;
    ANTENNAPARTIALMETALSIDEAREA 0.0312 LAYER M3  ;
    ANTENNAPARTIALCUTAREA 0.08 LAYER V3  ;
    ANTENNAPARTIALMETALAREA 22.72 LAYER M4  ;
    ANTENNAPARTIALMETALSIDEAREA 0.228 LAYER M4  ;
    ANTENNAMODEL OXIDE1 ;
    ANTENNAGATEAREA 0.3792 LAYER M4  ;
    ANTENNAMAXAREACAR 129.98 LAYER M4  ;
    ANTENNAMAXSIDEAREACAR 1.31857 LAYER M4  ;
    ANTENNAMAXCUTCAR 4.48718 LAYER V4  ;
    PORT
      LAYER M2 ;
        RECT 234.700000 349.400000 234.900000 350.000000 ;
    END
  END pe_in_pk_wrb_data__2_
  PIN pe_in_pk_wrb_data__1_
    DIRECTION INPUT ;
    USE SIGNAL ;
    ANTENNAPARTIALMETALAREA 5.26 LAYER M2  ;
    ANTENNAPARTIALMETALSIDEAREA 0.0526 LAYER M2  ;
    ANTENNAPARTIALCUTAREA 0.08 LAYER V2  ;
    ANTENNAPARTIALMETALAREA 0.44 LAYER M3  ;
    ANTENNAPARTIALMETALSIDEAREA 0.0048 LAYER M3  ;
    ANTENNAPARTIALCUTAREA 0.08 LAYER V3  ;
    ANTENNAPARTIALMETALAREA 28.48 LAYER M4  ;
    ANTENNAPARTIALMETALSIDEAREA 0.2856 LAYER M4  ;
    ANTENNAMODEL OXIDE1 ;
    ANTENNAGATEAREA 0.3792 LAYER M4  ;
    ANTENNAMAXAREACAR 102.055 LAYER M4  ;
    ANTENNAMAXSIDEAREACAR 1.02738 LAYER M4  ;
    ANTENNAMAXCUTCAR 4.48718 LAYER V4  ;
    PORT
      LAYER M2 ;
        RECT 224.700000 349.400000 224.900000 350.000000 ;
    END
  END pe_in_pk_wrb_data__1_
  PIN pe_in_pk_wrb_data__0_
    DIRECTION INPUT ;
    USE SIGNAL ;
    ANTENNAPARTIALMETALAREA 6.7 LAYER M2  ;
    ANTENNAPARTIALMETALSIDEAREA 0.067 LAYER M2  ;
    ANTENNAPARTIALCUTAREA 0.08 LAYER V2  ;
    ANTENNAPARTIALMETALAREA 0.84 LAYER M3  ;
    ANTENNAPARTIALMETALSIDEAREA 0.0088 LAYER M3  ;
    ANTENNAPARTIALCUTAREA 0.08 LAYER V3  ;
    ANTENNAPARTIALMETALAREA 26.28 LAYER M4  ;
    ANTENNAPARTIALMETALSIDEAREA 0.2632 LAYER M4  ;
    ANTENNAMODEL OXIDE1 ;
    ANTENNAGATEAREA 0.3792 LAYER M4  ;
    ANTENNAMAXAREACAR 111.483 LAYER M4  ;
    ANTENNAMAXSIDEAREACAR 1.12935 LAYER M4  ;
    ANTENNAMAXCUTCAR 3.20513 LAYER V4  ;
    PORT
      LAYER M2 ;
        RECT 214.700000 349.400000 214.900000 350.000000 ;
    END
  END pe_in_pk_wrb_data__0_
  PIN pe_in_pk_wrb_addr__3_
    DIRECTION INPUT ;
    USE SIGNAL ;
    ANTENNAPARTIALMETALAREA 4.7 LAYER M2  ;
    ANTENNAPARTIALMETALSIDEAREA 0.047 LAYER M2  ;
    ANTENNAPARTIALCUTAREA 0.08 LAYER V2  ;
    ANTENNAPARTIALMETALAREA 0.84 LAYER M3  ;
    ANTENNAPARTIALMETALSIDEAREA 0.0088 LAYER M3  ;
    ANTENNAMODEL OXIDE1 ;
    ANTENNAGATEAREA 0.264 LAYER M3  ;
    ANTENNAMAXAREACAR 5.50152 LAYER M3  ;
    ANTENNAMAXSIDEAREACAR 0.0554545 LAYER M3  ;
    ANTENNAPARTIALCUTAREA 0.08 LAYER V3  ;
    ANTENNAMAXCUTCAR 0.909091 LAYER V3  ;
    ANTENNAPARTIALMETALAREA 27.32 LAYER M4  ;
    ANTENNAPARTIALMETALSIDEAREA 0.2736 LAYER M4  ;
    ANTENNAGATEAREA 1.056 LAYER M4  ;
    ANTENNAMAXAREACAR 41.6758 LAYER M4  ;
    ANTENNAMAXSIDEAREACAR 0.417576 LAYER M4  ;
    ANTENNAMAXCUTCAR 0.909091 LAYER V4  ;
    PORT
      LAYER M2 ;
        RECT 204.700000 349.400000 204.900000 350.000000 ;
    END
  END pe_in_pk_wrb_addr__3_
  PIN pe_in_pk_wrb_addr__2_
    DIRECTION INPUT ;
    USE SIGNAL ;
    ANTENNAPARTIALMETALAREA 4.78 LAYER M2  ;
    ANTENNAPARTIALMETALSIDEAREA 0.0478 LAYER M2  ;
    ANTENNAPARTIALCUTAREA 0.08 LAYER V2  ;
    ANTENNAPARTIALMETALAREA 4.32 LAYER M3  ;
    ANTENNAPARTIALMETALSIDEAREA 0.044 LAYER M3  ;
    ANTENNAMODEL OXIDE1 ;
    ANTENNAGATEAREA 0.8136 LAYER M3  ;
    ANTENNAMAXAREACAR 14.1259 LAYER M3  ;
    ANTENNAMAXSIDEAREACAR 0.142056 LAYER M3  ;
    ANTENNAPARTIALCUTAREA 0.08 LAYER V3  ;
    ANTENNAMAXCUTCAR 1.38038 LAYER V3  ;
    ANTENNAPARTIALMETALAREA 25.92 LAYER M4  ;
    ANTENNAPARTIALMETALSIDEAREA 0.26 LAYER M4  ;
    ANTENNAGATEAREA 1.7808 LAYER M4  ;
    ANTENNAMAXAREACAR 28.6812 LAYER M4  ;
    ANTENNAMAXSIDEAREACAR 0.288058 LAYER M4  ;
    ANTENNAMAXCUTCAR 2.25225 LAYER V4  ;
    PORT
      LAYER M2 ;
        RECT 194.700000 349.400000 194.900000 350.000000 ;
    END
  END pe_in_pk_wrb_addr__2_
  PIN pe_in_pk_wrb_addr__1_
    DIRECTION INPUT ;
    USE SIGNAL ;
    ANTENNAPARTIALMETALAREA 4.74 LAYER M2  ;
    ANTENNAPARTIALMETALSIDEAREA 0.0478 LAYER M2  ;
    ANTENNAMODEL OXIDE1 ;
    ANTENNAGATEAREA 0.1608 LAYER M2  ;
    ANTENNAMAXAREACAR 30.2736 LAYER M2  ;
    ANTENNAMAXSIDEAREACAR 0.306219 LAYER M2  ;
    ANTENNAPARTIALCUTAREA 0.08 LAYER V2  ;
    ANTENNAMAXCUTCAR 0.746269 LAYER V2  ;
    ANTENNAPARTIALMETALAREA 0.76 LAYER M3  ;
    ANTENNAPARTIALMETALSIDEAREA 0.008 LAYER M3  ;
    ANTENNAGATEAREA 0.3384 LAYER M3  ;
    ANTENNAMAXAREACAR 32.5195 LAYER M3  ;
    ANTENNAMAXSIDEAREACAR 0.32986 LAYER M3  ;
    ANTENNAMAXCUTCAR 0.746269 LAYER V3  ;
    PORT
      LAYER M2 ;
        RECT 184.700000 349.400000 184.900000 350.000000 ;
    END
  END pe_in_pk_wrb_addr__1_
  PIN pe_in_pk_wrb_addr__0_
    DIRECTION INPUT ;
    USE SIGNAL ;
    ANTENNAPARTIALMETALAREA 4.14 LAYER M2  ;
    ANTENNAPARTIALMETALSIDEAREA 0.0414 LAYER M2  ;
    ANTENNAPARTIALCUTAREA 0.08 LAYER V2  ;
    ANTENNAPARTIALMETALAREA 1.4 LAYER M3  ;
    ANTENNAPARTIALMETALSIDEAREA 0.0144 LAYER M3  ;
    ANTENNAMODEL OXIDE1 ;
    ANTENNAGATEAREA 0.1776 LAYER M3  ;
    ANTENNAMAXAREACAR 11.0011 LAYER M3  ;
    ANTENNAMAXSIDEAREACAR 0.113739 LAYER M3  ;
    ANTENNAPARTIALCUTAREA 0.08 LAYER V3  ;
    ANTENNAMAXCUTCAR 1.35135 LAYER V3  ;
    ANTENNAPARTIALMETALAREA 1.56 LAYER M4  ;
    ANTENNAPARTIALMETALSIDEAREA 0.016 LAYER M4  ;
    ANTENNAGATEAREA 0.7512 LAYER M4  ;
    ANTENNAMAXAREACAR 14.2696 LAYER M4  ;
    ANTENNAMAXSIDEAREACAR 0.148447 LAYER M4  ;
    ANTENNAMAXCUTCAR 1.35135 LAYER V4  ;
    PORT
      LAYER M2 ;
        RECT 174.700000 349.400000 174.900000 350.000000 ;
    END
  END pe_in_pk_wrb_addr__0_
  PIN pe_in_pk_wrb__3_
    DIRECTION INPUT ;
    USE SIGNAL ;
    ANTENNAPARTIALMETALAREA 3.9 LAYER M2  ;
    ANTENNAPARTIALMETALSIDEAREA 0.039 LAYER M2  ;
    ANTENNAPARTIALCUTAREA 0.08 LAYER V2  ;
    ANTENNAPARTIALMETALAREA 3.16 LAYER M3  ;
    ANTENNAPARTIALMETALSIDEAREA 0.0328 LAYER M3  ;
    ANTENNAMODEL OXIDE1 ;
    ANTENNAGATEAREA 0.4608 LAYER M3  ;
    ANTENNAMAXAREACAR 13.5236 LAYER M3  ;
    ANTENNAMAXSIDEAREACAR 0.141073 LAYER M3  ;
    ANTENNAMAXCUTCAR 1.34409 LAYER V3  ;
    PORT
      LAYER M2 ;
        RECT 164.700000 349.400000 164.900000 350.000000 ;
    END
  END pe_in_pk_wrb__3_
  PIN pe_in_pk_wrb__2_
    DIRECTION INPUT ;
    USE SIGNAL ;
    ANTENNAPARTIALMETALAREA 3.58 LAYER M2  ;
    ANTENNAPARTIALMETALSIDEAREA 0.0358 LAYER M2  ;
    ANTENNAPARTIALCUTAREA 0.08 LAYER V2  ;
    ANTENNAPARTIALMETALAREA 11.16 LAYER M3  ;
    ANTENNAPARTIALMETALSIDEAREA 0.112 LAYER M3  ;
    ANTENNAPARTIALCUTAREA 0.08 LAYER V3  ;
    ANTENNAPARTIALMETALAREA 14.76 LAYER M4  ;
    ANTENNAPARTIALMETALSIDEAREA 0.148 LAYER M4  ;
    ANTENNAMODEL OXIDE1 ;
    ANTENNAGATEAREA 0.4608 LAYER M4  ;
    ANTENNAMAXAREACAR 38.6838 LAYER M4  ;
    ANTENNAMAXSIDEAREACAR 0.3904 LAYER M4  ;
    ANTENNAMAXCUTCAR 0.980063 LAYER V4  ;
    PORT
      LAYER M2 ;
        RECT 154.700000 349.400000 154.900000 350.000000 ;
    END
  END pe_in_pk_wrb__2_
  PIN pe_in_pk_wrb__1_
    DIRECTION INPUT ;
    USE SIGNAL ;
    ANTENNAPARTIALMETALAREA 2.7 LAYER M2  ;
    ANTENNAPARTIALMETALSIDEAREA 0.027 LAYER M2  ;
    ANTENNAPARTIALCUTAREA 0.08 LAYER V2  ;
    ANTENNAPARTIALMETALAREA 8.68 LAYER M3  ;
    ANTENNAPARTIALMETALSIDEAREA 0.0872 LAYER M3  ;
    ANTENNAPARTIALCUTAREA 0.08 LAYER V3  ;
    ANTENNAPARTIALMETALAREA 30.44 LAYER M4  ;
    ANTENNAPARTIALMETALSIDEAREA 0.3048 LAYER M4  ;
    ANTENNAMODEL OXIDE1 ;
    ANTENNAGATEAREA 0.4608 LAYER M4  ;
    ANTENNAMAXAREACAR 71.7149 LAYER M4  ;
    ANTENNAMAXSIDEAREACAR 0.724362 LAYER M4  ;
    ANTENNAMAXCUTCAR 1.34409 LAYER V4  ;
    PORT
      LAYER M2 ;
        RECT 144.700000 349.400000 144.900000 350.000000 ;
    END
  END pe_in_pk_wrb__1_
  PIN pe_in_pk_wrb__0_
    DIRECTION INPUT ;
    USE SIGNAL ;
    ANTENNAPARTIALMETALAREA 2.86 LAYER M2  ;
    ANTENNAPARTIALMETALSIDEAREA 0.0286 LAYER M2  ;
    ANTENNAPARTIALCUTAREA 0.08 LAYER V2  ;
    ANTENNAPARTIALMETALAREA 18.52 LAYER M3  ;
    ANTENNAPARTIALMETALSIDEAREA 0.1856 LAYER M3  ;
    ANTENNAPARTIALCUTAREA 0.08 LAYER V3  ;
    ANTENNAPARTIALMETALAREA 34.36 LAYER M4  ;
    ANTENNAPARTIALMETALSIDEAREA 0.344 LAYER M4  ;
    ANTENNAMODEL OXIDE1 ;
    ANTENNAGATEAREA 0.4608 LAYER M4  ;
    ANTENNAMAXAREACAR 82.1232 LAYER M4  ;
    ANTENNAMAXSIDEAREACAR 0.826624 LAYER M4  ;
    ANTENNAMAXCUTCAR 0.980063 LAYER V4  ;
    PORT
      LAYER M2 ;
        RECT 134.700000 349.400000 134.900000 350.000000 ;
    END
  END pe_in_pk_wrb__0_
  PIN pe_in_pk_rdb_addr__3_
    DIRECTION INPUT ;
    USE SIGNAL ;
    ANTENNAPARTIALMETALAREA 2.7 LAYER M2  ;
    ANTENNAPARTIALMETALSIDEAREA 0.027 LAYER M2  ;
    ANTENNAPARTIALCUTAREA 0.08 LAYER V2  ;
    ANTENNAPARTIALMETALAREA 9.4 LAYER M3  ;
    ANTENNAPARTIALMETALSIDEAREA 0.0944 LAYER M3  ;
    ANTENNAPARTIALCUTAREA 0.08 LAYER V3  ;
    ANTENNAPARTIALMETALAREA 33.2 LAYER M4  ;
    ANTENNAPARTIALMETALSIDEAREA 0.3328 LAYER M4  ;
    ANTENNAMODEL OXIDE1 ;
    ANTENNAGATEAREA 1.1304 LAYER M4  ;
    ANTENNAMAXAREACAR 73.3278 LAYER M4  ;
    ANTENNAMAXSIDEAREACAR 0.737551 LAYER M4  ;
    ANTENNAMAXCUTCAR 3.72792 LAYER V4  ;
    PORT
      LAYER M2 ;
        RECT 124.700000 349.400000 124.900000 350.000000 ;
    END
  END pe_in_pk_rdb_addr__3_
  PIN pe_in_pk_rdb_addr__2_
    DIRECTION INPUT ;
    USE SIGNAL ;
    ANTENNAPARTIALMETALAREA 0.16 LAYER M2  ;
    ANTENNAPARTIALMETALSIDEAREA 0.0016 LAYER M2  ;
    ANTENNAPARTIALCUTAREA 0.08 LAYER V2  ;
    ANTENNAPARTIALMETALAREA 10.12 LAYER M3  ;
    ANTENNAPARTIALMETALSIDEAREA 0.1016 LAYER M3  ;
    ANTENNAPARTIALCUTAREA 0.08 LAYER V3  ;
    ANTENNAPARTIALMETALAREA 44.48 LAYER M4  ;
    ANTENNAPARTIALMETALSIDEAREA 0.4472 LAYER M4  ;
    ANTENNAMODEL OXIDE1 ;
    ANTENNAGATEAREA 2.472 LAYER M4  ;
    ANTENNAMAXAREACAR 65.0791 LAYER M4  ;
    ANTENNAMAXSIDEAREACAR 0.657821 LAYER M4  ;
    ANTENNAMAXCUTCAR 1.6983 LAYER V4  ;
    PORT
      LAYER M2 ;
        RECT 114.700000 349.400000 114.900000 350.000000 ;
    END
  END pe_in_pk_rdb_addr__2_
  PIN pe_in_pk_rdb_addr__1_
    DIRECTION INPUT ;
    USE SIGNAL ;
    ANTENNAPARTIALMETALAREA 6.06 LAYER M2  ;
    ANTENNAPARTIALMETALSIDEAREA 0.0606 LAYER M2  ;
    ANTENNAPARTIALCUTAREA 0.08 LAYER V2  ;
    ANTENNAPARTIALMETALAREA 3.08 LAYER M3  ;
    ANTENNAPARTIALMETALSIDEAREA 0.0312 LAYER M3  ;
    ANTENNAMODEL OXIDE1 ;
    ANTENNAGATEAREA 0.7992 LAYER M3  ;
    ANTENNAMAXAREACAR 10.0901 LAYER M3  ;
    ANTENNAMAXSIDEAREACAR 0.1 LAYER M3  ;
    ANTENNAMAXCUTCAR 0.15015 LAYER V3  ;
    PORT
      LAYER M2 ;
        RECT 104.700000 349.400000 104.900000 350.000000 ;
    END
  END pe_in_pk_rdb_addr__1_
  PIN pe_in_pk_rdb_addr__0_
    DIRECTION INPUT ;
    USE SIGNAL ;
    ANTENNAPARTIALMETALAREA 11.42 LAYER M2  ;
    ANTENNAPARTIALMETALSIDEAREA 0.1142 LAYER M2  ;
    ANTENNAPARTIALCUTAREA 0.08 LAYER V2  ;
    ANTENNAPARTIALMETALAREA 9.64 LAYER M3  ;
    ANTENNAPARTIALMETALSIDEAREA 0.0968 LAYER M3  ;
    ANTENNAMODEL OXIDE1 ;
    ANTENNAGATEAREA 0.576 LAYER M3  ;
    ANTENNAMAXAREACAR 19.3588 LAYER M3  ;
    ANTENNAMAXSIDEAREACAR 0.193207 LAYER M3  ;
    ANTENNAMAXCUTCAR 0.606061 LAYER V3  ;
    PORT
      LAYER M2 ;
        RECT 94.700000 349.400000 94.900000 350.000000 ;
    END
  END pe_in_pk_rdb_addr__0_
  PIN pe_out_pk_PE_state__2_
    DIRECTION OUTPUT ;
    USE SIGNAL ;
    ANTENNAPARTIALMETALAREA 1.74 LAYER M2  ;
    ANTENNAPARTIALMETALSIDEAREA 0.0174 LAYER M2  ;
    ANTENNAPARTIALCUTAREA 0.08 LAYER V2  ;
    ANTENNADIFFAREA 2.014 LAYER M3  ;
    ANTENNAPARTIALMETALAREA 5.88 LAYER M3  ;
    ANTENNAPARTIALMETALSIDEAREA 0.0592 LAYER M3  ;
    PORT
      LAYER M2 ;
        RECT 75.100000 0.000000 75.300000 0.600000 ;
    END
  END pe_out_pk_PE_state__2_
  PIN pe_out_pk_PE_state__1_
    DIRECTION OUTPUT ;
    USE SIGNAL ;
    ANTENNAPARTIALMETALAREA 3.42 LAYER M2  ;
    ANTENNAPARTIALMETALSIDEAREA 0.0342 LAYER M2  ;
    ANTENNAPARTIALCUTAREA 0.08 LAYER V2  ;
    ANTENNADIFFAREA 2.014 LAYER M3  ;
    ANTENNAPARTIALMETALAREA 1.88 LAYER M3  ;
    ANTENNAPARTIALMETALSIDEAREA 0.0192 LAYER M3  ;
    PORT
      LAYER M2 ;
        RECT 95.100000 0.000000 95.300000 0.600000 ;
    END
  END pe_out_pk_PE_state__1_
  PIN pe_out_pk_PE_state__0_
    DIRECTION OUTPUT ;
    USE SIGNAL ;
    ANTENNAPARTIALMETALAREA 2.86 LAYER M2  ;
    ANTENNAPARTIALMETALSIDEAREA 0.0286 LAYER M2  ;
    ANTENNAPARTIALCUTAREA 0.08 LAYER V2  ;
    ANTENNADIFFAREA 2.014 LAYER M3  ;
    ANTENNAPARTIALMETALAREA 0.92 LAYER M3  ;
    ANTENNAPARTIALMETALSIDEAREA 0.0096 LAYER M3  ;
    PORT
      LAYER M2 ;
        RECT 115.100000 0.000000 115.300000 0.600000 ;
    END
  END pe_out_pk_PE_state__0_
  PIN pe_out_pk_data__7_
    DIRECTION OUTPUT ;
    USE SIGNAL ;
    ANTENNAPARTIALMETALAREA 2.86 LAYER M2  ;
    ANTENNAPARTIALMETALSIDEAREA 0.0286 LAYER M2  ;
    ANTENNAPARTIALCUTAREA 0.08 LAYER V2  ;
    ANTENNADIFFAREA 2.014 LAYER M3  ;
    ANTENNAPARTIALMETALAREA 1.48 LAYER M3  ;
    ANTENNAPARTIALMETALSIDEAREA 0.0152 LAYER M3  ;
    PORT
      LAYER M2 ;
        RECT 135.100000 0.000000 135.300000 0.600000 ;
    END
  END pe_out_pk_data__7_
  PIN pe_out_pk_data__6_
    DIRECTION OUTPUT ;
    USE SIGNAL ;
    ANTENNAPARTIALMETALAREA 2.22 LAYER M2  ;
    ANTENNAPARTIALMETALSIDEAREA 0.0222 LAYER M2  ;
    ANTENNAPARTIALCUTAREA 0.08 LAYER V2  ;
    ANTENNADIFFAREA 2.014 LAYER M3  ;
    ANTENNAPARTIALMETALAREA 4.04 LAYER M3  ;
    ANTENNAPARTIALMETALSIDEAREA 0.0408 LAYER M3  ;
    PORT
      LAYER M2 ;
        RECT 155.100000 0.000000 155.300000 0.600000 ;
    END
  END pe_out_pk_data__6_
  PIN pe_out_pk_data__5_
    DIRECTION OUTPUT ;
    USE SIGNAL ;
    ANTENNAPARTIALMETALAREA 1.26 LAYER M2  ;
    ANTENNAPARTIALMETALSIDEAREA 0.0126 LAYER M2  ;
    ANTENNAPARTIALCUTAREA 0.08 LAYER V2  ;
    ANTENNADIFFAREA 2.014 LAYER M3  ;
    ANTENNAPARTIALMETALAREA 6.36 LAYER M3  ;
    ANTENNAPARTIALMETALSIDEAREA 0.064 LAYER M3  ;
    PORT
      LAYER M2 ;
        RECT 175.100000 0.000000 175.300000 0.600000 ;
    END
  END pe_out_pk_data__5_
  PIN pe_out_pk_data__4_
    DIRECTION OUTPUT ;
    USE SIGNAL ;
    ANTENNAPARTIALMETALAREA 5.18 LAYER M2  ;
    ANTENNAPARTIALMETALSIDEAREA 0.0518 LAYER M2  ;
    ANTENNAPARTIALCUTAREA 0.08 LAYER V2  ;
    ANTENNADIFFAREA 2.014 LAYER M3  ;
    ANTENNAPARTIALMETALAREA 4.52 LAYER M3  ;
    ANTENNAPARTIALMETALSIDEAREA 0.0456 LAYER M3  ;
    PORT
      LAYER M2 ;
        RECT 195.100000 0.000000 195.300000 0.600000 ;
    END
  END pe_out_pk_data__4_
  PIN pe_out_pk_data__3_
    DIRECTION OUTPUT ;
    USE SIGNAL ;
    ANTENNAPARTIALMETALAREA 4.54 LAYER M2  ;
    ANTENNAPARTIALMETALSIDEAREA 0.0454 LAYER M2  ;
    ANTENNAPARTIALCUTAREA 0.08 LAYER V2  ;
    ANTENNADIFFAREA 2.014 LAYER M3  ;
    ANTENNAPARTIALMETALAREA 8.52 LAYER M3  ;
    ANTENNAPARTIALMETALSIDEAREA 0.0856 LAYER M3  ;
    PORT
      LAYER M2 ;
        RECT 215.100000 0.000000 215.300000 0.600000 ;
    END
  END pe_out_pk_data__3_
  PIN pe_out_pk_data__2_
    DIRECTION OUTPUT ;
    USE SIGNAL ;
    ANTENNAPARTIALMETALAREA 1.74 LAYER M2  ;
    ANTENNAPARTIALMETALSIDEAREA 0.0174 LAYER M2  ;
    ANTENNAPARTIALCUTAREA 0.08 LAYER V2  ;
    ANTENNADIFFAREA 2.014 LAYER M3  ;
    ANTENNAPARTIALMETALAREA 12.88 LAYER M3  ;
    ANTENNAPARTIALMETALSIDEAREA 0.1296 LAYER M3  ;
    PORT
      LAYER M2 ;
        RECT 235.100000 0.000000 235.300000 0.600000 ;
    END
  END pe_out_pk_data__2_
  PIN pe_out_pk_data__1_
    DIRECTION OUTPUT ;
    USE SIGNAL ;
    ANTENNAPARTIALMETALAREA 2.54 LAYER M2  ;
    ANTENNAPARTIALMETALSIDEAREA 0.0254 LAYER M2  ;
    ANTENNAPARTIALCUTAREA 0.08 LAYER V2  ;
    ANTENNADIFFAREA 2.014 LAYER M3  ;
    ANTENNAPARTIALMETALAREA 16.68 LAYER M3  ;
    ANTENNAPARTIALMETALSIDEAREA 0.1672 LAYER M3  ;
    PORT
      LAYER M2 ;
        RECT 255.100000 0.000000 255.300000 0.600000 ;
    END
  END pe_out_pk_data__1_
  PIN pe_out_pk_data__0_
    DIRECTION OUTPUT ;
    USE SIGNAL ;
    ANTENNAPARTIALMETALAREA 1.42 LAYER M2  ;
    ANTENNAPARTIALMETALSIDEAREA 0.0142 LAYER M2  ;
    ANTENNAPARTIALCUTAREA 0.08 LAYER V2  ;
    ANTENNADIFFAREA 2.014 LAYER M3  ;
    ANTENNAPARTIALMETALAREA 20.76 LAYER M3  ;
    ANTENNAPARTIALMETALSIDEAREA 0.208 LAYER M3  ;
    PORT
      LAYER M2 ;
        RECT 275.100000 0.000000 275.300000 0.600000 ;
    END
  END pe_out_pk_data__0_
  PIN VSS
    DIRECTION INOUT ;
    USE GROUND ;

# P/G power stripe data as pin
    PORT
      LAYER M4 ;
        RECT 86.000000 1.000000 88.000000 348.400000 ;
        RECT 56.000000 1.000000 58.000000 348.400000 ;
        RECT 26.000000 1.000000 28.000000 348.400000 ;
        RECT 1.000000 1.000000 3.000000 348.400000 ;
        RECT 146.000000 1.000000 148.000000 348.400000 ;
        RECT 116.000000 1.000000 118.000000 348.400000 ;
        RECT 236.000000 1.000000 238.000000 348.400000 ;
        RECT 206.000000 1.000000 208.000000 348.400000 ;
        RECT 176.000000 1.000000 178.000000 348.400000 ;
        RECT 266.000000 1.000000 268.000000 348.400000 ;
        RECT 296.000000 1.000000 298.000000 348.400000 ;
        RECT 326.000000 1.000000 328.000000 348.400000 ;
        RECT 347.000000 1.000000 349.000000 348.400000 ;
    END
# end of P/G power stripe data as pin

  END VSS
  PIN VDD
    DIRECTION INOUT ;
    USE POWER ;

# P/G power stripe data as pin
    PORT
      LAYER M4 ;
        RECT 82.000000 4.000000 84.000000 345.400000 ;
        RECT 52.000000 4.000000 54.000000 345.400000 ;
        RECT 22.000000 4.000000 24.000000 345.400000 ;
        RECT 4.000000 4.000000 6.000000 345.400000 ;
        RECT 172.000000 4.000000 174.000000 345.400000 ;
        RECT 142.000000 4.000000 144.000000 345.400000 ;
        RECT 112.000000 4.000000 114.000000 345.400000 ;
        RECT 262.000000 4.000000 264.000000 345.400000 ;
        RECT 232.000000 4.000000 234.000000 345.400000 ;
        RECT 202.000000 4.000000 204.000000 345.400000 ;
        RECT 292.000000 4.000000 294.000000 345.400000 ;
        RECT 322.000000 4.000000 324.000000 345.400000 ;
        RECT 344.000000 4.000000 346.000000 345.400000 ;
    END
# end of P/G power stripe data as pin

  END VDD
  OBS
    LAYER M1 ;
      RECT 0.000000 0.000000 350.000000 350.000000 ;
    LAYER M2 ;
      RECT 286.820000 347.480000 350.000000 350.000000 ;
      RECT 276.820000 347.480000 282.780000 350.000000 ;
      RECT 266.820000 347.480000 272.780000 350.000000 ;
      RECT 256.820000 347.480000 262.780000 350.000000 ;
      RECT 246.820000 347.480000 252.780000 350.000000 ;
      RECT 236.820000 347.480000 242.780000 350.000000 ;
      RECT 226.820000 347.480000 232.780000 350.000000 ;
      RECT 216.820000 347.480000 222.780000 350.000000 ;
      RECT 206.820000 347.480000 212.780000 350.000000 ;
      RECT 196.820000 347.480000 202.780000 350.000000 ;
      RECT 186.820000 347.480000 192.780000 350.000000 ;
      RECT 176.820000 347.480000 182.780000 350.000000 ;
      RECT 166.820000 347.480000 172.780000 350.000000 ;
      RECT 156.820000 347.480000 162.780000 350.000000 ;
      RECT 146.820000 347.480000 152.780000 350.000000 ;
      RECT 136.820000 347.480000 142.780000 350.000000 ;
      RECT 126.820000 347.480000 132.780000 350.000000 ;
      RECT 116.820000 347.480000 122.780000 350.000000 ;
      RECT 106.820000 347.480000 112.780000 350.000000 ;
      RECT 96.820000 347.480000 102.780000 350.000000 ;
      RECT 86.820000 347.480000 92.780000 350.000000 ;
      RECT 76.820000 347.480000 82.780000 350.000000 ;
      RECT 66.820000 347.480000 72.780000 350.000000 ;
      RECT 0.000000 347.480000 62.780000 350.000000 ;
      RECT 0.000000 2.520000 350.000000 347.480000 ;
      RECT 277.220000 0.000000 350.000000 2.520000 ;
      RECT 257.220000 0.000000 273.180000 2.520000 ;
      RECT 237.220000 0.000000 253.180000 2.520000 ;
      RECT 217.220000 0.000000 233.180000 2.520000 ;
      RECT 197.220000 0.000000 213.180000 2.520000 ;
      RECT 177.220000 0.000000 193.180000 2.520000 ;
      RECT 157.220000 0.000000 173.180000 2.520000 ;
      RECT 137.220000 0.000000 153.180000 2.520000 ;
      RECT 117.220000 0.000000 133.180000 2.520000 ;
      RECT 97.220000 0.000000 113.180000 2.520000 ;
      RECT 77.220000 0.000000 93.180000 2.520000 ;
      RECT 0.000000 0.000000 73.180000 2.520000 ;
    LAYER M3 ;
      RECT 0.000000 300.820000 350.000000 350.000000 ;
      RECT 2.520000 296.780000 350.000000 300.820000 ;
      RECT 0.000000 292.820000 350.000000 296.780000 ;
      RECT 2.520000 288.780000 350.000000 292.820000 ;
      RECT 0.000000 284.820000 350.000000 288.780000 ;
      RECT 2.520000 280.780000 350.000000 284.820000 ;
      RECT 0.000000 276.820000 350.000000 280.780000 ;
      RECT 2.520000 272.780000 350.000000 276.820000 ;
      RECT 0.000000 268.820000 350.000000 272.780000 ;
      RECT 2.520000 264.780000 350.000000 268.820000 ;
      RECT 0.000000 260.820000 350.000000 264.780000 ;
      RECT 2.520000 256.780000 350.000000 260.820000 ;
      RECT 0.000000 252.820000 350.000000 256.780000 ;
      RECT 2.520000 248.780000 350.000000 252.820000 ;
      RECT 0.000000 244.820000 350.000000 248.780000 ;
      RECT 2.520000 240.780000 350.000000 244.820000 ;
      RECT 0.000000 236.820000 350.000000 240.780000 ;
      RECT 2.520000 232.780000 350.000000 236.820000 ;
      RECT 0.000000 228.820000 350.000000 232.780000 ;
      RECT 2.520000 224.780000 350.000000 228.820000 ;
      RECT 0.000000 220.820000 350.000000 224.780000 ;
      RECT 2.520000 216.780000 350.000000 220.820000 ;
      RECT 0.000000 212.820000 350.000000 216.780000 ;
      RECT 2.520000 208.780000 350.000000 212.820000 ;
      RECT 0.000000 204.820000 350.000000 208.780000 ;
      RECT 2.520000 200.780000 350.000000 204.820000 ;
      RECT 0.000000 196.820000 350.000000 200.780000 ;
      RECT 2.520000 192.780000 350.000000 196.820000 ;
      RECT 0.000000 188.820000 350.000000 192.780000 ;
      RECT 2.520000 184.780000 350.000000 188.820000 ;
      RECT 0.000000 180.820000 350.000000 184.780000 ;
      RECT 2.520000 176.780000 350.000000 180.820000 ;
      RECT 0.000000 172.820000 350.000000 176.780000 ;
      RECT 2.520000 168.780000 350.000000 172.820000 ;
      RECT 0.000000 164.820000 350.000000 168.780000 ;
      RECT 2.520000 160.780000 350.000000 164.820000 ;
      RECT 0.000000 156.820000 350.000000 160.780000 ;
      RECT 2.520000 152.780000 350.000000 156.820000 ;
      RECT 0.000000 148.820000 350.000000 152.780000 ;
      RECT 2.520000 144.780000 350.000000 148.820000 ;
      RECT 0.000000 140.820000 350.000000 144.780000 ;
      RECT 2.520000 136.780000 350.000000 140.820000 ;
      RECT 0.000000 132.820000 350.000000 136.780000 ;
      RECT 2.520000 128.780000 350.000000 132.820000 ;
      RECT 0.000000 124.820000 350.000000 128.780000 ;
      RECT 2.520000 120.780000 350.000000 124.820000 ;
      RECT 0.000000 116.820000 350.000000 120.780000 ;
      RECT 2.520000 112.780000 350.000000 116.820000 ;
      RECT 0.000000 108.820000 350.000000 112.780000 ;
      RECT 2.520000 104.780000 350.000000 108.820000 ;
      RECT 0.000000 100.820000 350.000000 104.780000 ;
      RECT 2.520000 96.780000 350.000000 100.820000 ;
      RECT 0.000000 92.820000 350.000000 96.780000 ;
      RECT 2.520000 88.780000 350.000000 92.820000 ;
      RECT 0.000000 84.820000 350.000000 88.780000 ;
      RECT 2.520000 80.780000 350.000000 84.820000 ;
      RECT 0.000000 76.820000 350.000000 80.780000 ;
      RECT 2.520000 72.780000 350.000000 76.820000 ;
      RECT 0.000000 68.820000 350.000000 72.780000 ;
      RECT 2.520000 64.780000 350.000000 68.820000 ;
      RECT 0.000000 60.820000 350.000000 64.780000 ;
      RECT 2.520000 56.780000 350.000000 60.820000 ;
      RECT 0.000000 52.820000 350.000000 56.780000 ;
      RECT 2.520000 48.780000 350.000000 52.820000 ;
      RECT 0.000000 22.020000 350.000000 48.780000 ;
      RECT 2.520000 17.980000 350.000000 22.020000 ;
      RECT 0.000000 12.020000 350.000000 17.980000 ;
      RECT 2.520000 7.980000 350.000000 12.020000 ;
      RECT 0.000000 0.000000 350.000000 7.980000 ;
    LAYER M4 ;
      RECT 329.920000 347.320000 345.080000 350.000000 ;
      RECT 299.920000 347.320000 324.080000 350.000000 ;
      RECT 269.920000 347.320000 294.080000 350.000000 ;
      RECT 239.920000 347.320000 264.080000 350.000000 ;
      RECT 209.920000 347.320000 234.080000 350.000000 ;
      RECT 179.920000 347.320000 204.080000 350.000000 ;
      RECT 149.920000 347.320000 174.080000 350.000000 ;
      RECT 119.920000 347.320000 144.080000 350.000000 ;
      RECT 89.920000 347.320000 114.080000 350.000000 ;
      RECT 59.920000 347.320000 84.080000 350.000000 ;
      RECT 29.920000 347.320000 54.080000 350.000000 ;
      RECT 4.920000 347.320000 24.080000 350.000000 ;
      RECT 329.920000 2.080000 342.080000 347.320000 ;
      RECT 299.920000 2.080000 320.080000 347.320000 ;
      RECT 269.920000 2.080000 290.080000 347.320000 ;
      RECT 239.920000 2.080000 260.080000 347.320000 ;
      RECT 209.920000 2.080000 230.080000 347.320000 ;
      RECT 179.920000 2.080000 200.080000 347.320000 ;
      RECT 149.920000 2.080000 170.080000 347.320000 ;
      RECT 119.920000 2.080000 140.080000 347.320000 ;
      RECT 89.920000 2.080000 110.080000 347.320000 ;
      RECT 59.920000 2.080000 80.080000 347.320000 ;
      RECT 29.920000 2.080000 50.080000 347.320000 ;
      RECT 7.920000 2.080000 20.080000 347.320000 ;
      RECT 329.920000 0.000000 345.080000 2.080000 ;
      RECT 299.920000 0.000000 324.080000 2.080000 ;
      RECT 269.920000 0.000000 294.080000 2.080000 ;
      RECT 239.920000 0.000000 264.080000 2.080000 ;
      RECT 209.920000 0.000000 234.080000 2.080000 ;
      RECT 179.920000 0.000000 204.080000 2.080000 ;
      RECT 149.920000 0.000000 174.080000 2.080000 ;
      RECT 119.920000 0.000000 144.080000 2.080000 ;
      RECT 89.920000 0.000000 114.080000 2.080000 ;
      RECT 59.920000 0.000000 84.080000 2.080000 ;
      RECT 29.920000 0.000000 54.080000 2.080000 ;
      RECT 4.920000 0.000000 24.080000 2.080000 ;
  END
END PE_top

END LIBRARY
